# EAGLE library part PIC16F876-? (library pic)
PIC 16F876, 28 pin, 8K prog, 256 EEPROM, USART, MSSP, 2 CCP, timer 0-2, 5x 10-bit A/D, 368 RAM

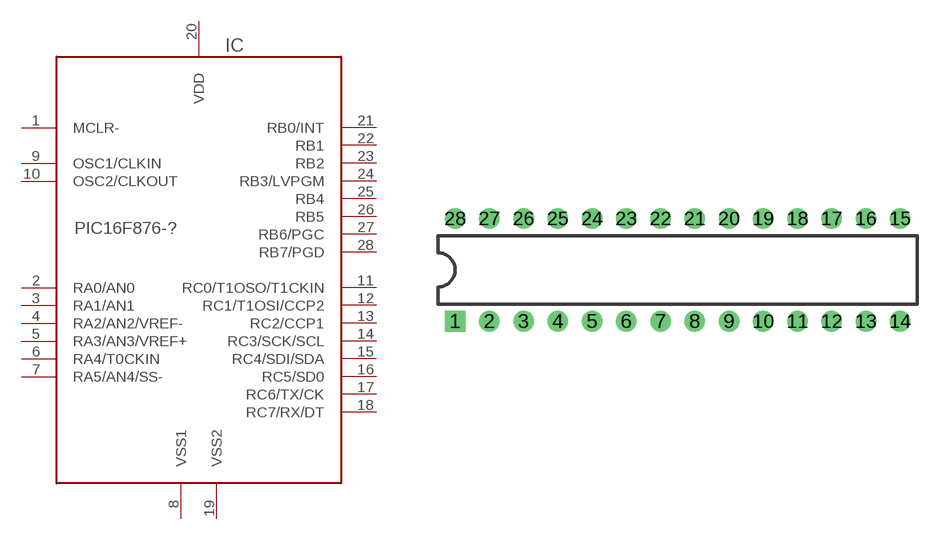
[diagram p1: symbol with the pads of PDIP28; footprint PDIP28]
Designator prefix IC

## PIC16F876-SP  [PDIP28]
1  MCLR-  in
2  RA0/AN0
3  RA1/AN1
4  RA2/AN2/VREF-
5  RA3/AN3/VREF+
6  RA4/T0CKIN  oc
7  RA5/AN4/SS-
8  VSS1  pwr
9  OSC1/CLKIN  in
10  OSC2/CLKOUT  out
11  RC0/T1OSO/T1CKIN
12  RC1/T1OSI/CCP2
13  RC2/CCP1
14  RC3/SCK/SCL
15  RC4/SDI/SDA
16  RC5/SD0
17  RC6/TX/CK
18  RC7/RX/DT
19  VSS2  pwr
20  VDD  pwr
21  RB0/INT
22  RB1
23  RB2
24  RB3/LVPGM
25  RB4
26  RB5
27  RB6/PGC
28  RB7/PGD

## Footprint PDIP28 (pad centres in mm)
28 pin skinny DIP (SP suffix)
drill 0.737 pad 1.524 square: 1 -17.78,-3.81
drill 0.737 pad 1.524 round: 2 -15.24,-3.81; 3 -12.7,-3.81; 4 -10.16,-3.81; 5 -7.62,-3.81; 6 -5.08,-3.81; 7 -2.54,-3.81; 8 0,-3.81; 9 2.54,-3.81; 10 5.08,-3.81; 11 7.62,-3.81; 12 10.16,-3.81; 13 12.7,-3.81; 14 15.24,-3.81; 15 15.24,3.81; 16 12.7,3.81; 17 10.16,3.81; 18 7.62,3.81; 19 5.08,3.81; 20 2.54,3.81; 21 0,3.81; 22 -2.54,3.81; 23 -5.08,3.81; 24 -7.62,3.81; 25 -10.16,3.81; 26 -12.7,3.81; 27 -15.24,3.81; 28 -17.78,3.81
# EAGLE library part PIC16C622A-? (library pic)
18/20 pin, 2K prog, 2 comp, 128 RAM

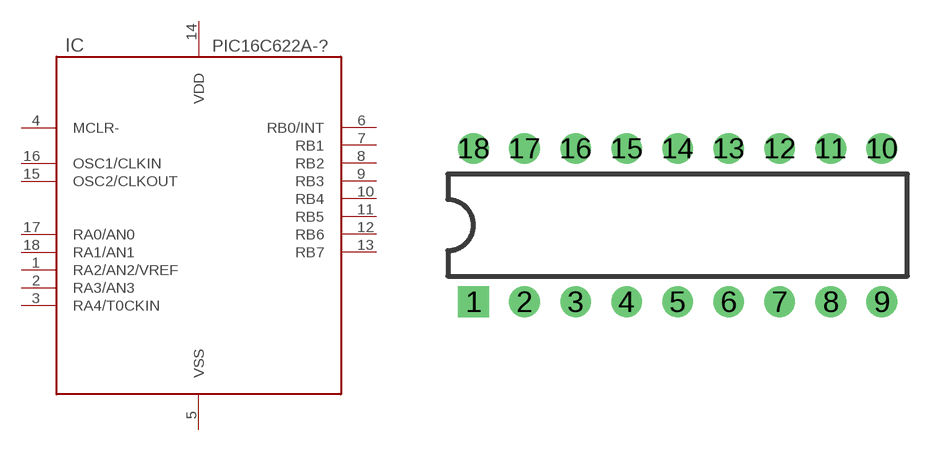
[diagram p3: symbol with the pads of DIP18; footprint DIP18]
Designator prefix IC

## PIC16C622A-P  [DIP18]
1  RA2/AN2/VREF
2  RA3/AN3
3  RA4/T0CKIN
4  MCLR-  in
5  VSS  pwr
6  RB0/INT
7  RB1
8  RB2
9  RB3
10  RB4
11  RB5
12  RB6
13  RB7
14  VDD  pwr
15  OSC2/CLKOUT  out
16  OSC1/CLKIN  in
17  RA0/AN0
18  RA1/AN1

## Footprint DIP18 (pad centres in mm)
18 pin DIP package, P suffix
drill 0.737 pad 1.524 square: 1 -10.16,-3.81
drill 0.737 pad 1.524 round: 2 -7.62,-3.81; 3 -5.08,-3.81; 4 -2.54,-3.81; 5 0,-3.81; 6 2.54,-3.81; 7 5.08,-3.81; 8 7.62,-3.81; 9 10.16,-3.81; 10 10.16,3.81; 11 7.62,3.81; 12 5.08,3.81; 13 2.54,3.81; 14 0,3.81; 15 -2.54,3.81; 16 -5.08,3.81; 17 -7.62,3.81; 18 -10.16,3.81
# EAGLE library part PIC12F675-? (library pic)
8 pins, 1K prog, 128 EEPROM, 1 comp, A/D

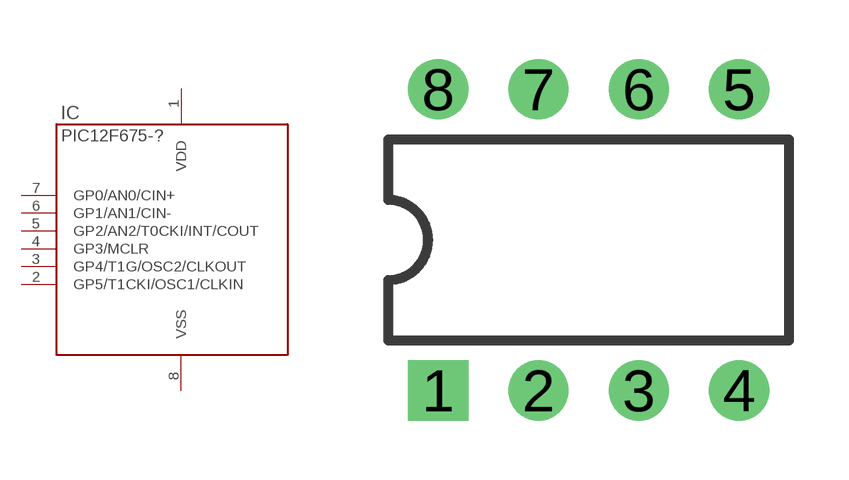
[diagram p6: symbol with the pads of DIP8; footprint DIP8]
Designator prefix IC

## PIC12F675-P  [DIP8]
1  VDD  pwr
2  GP5/T1CKI/OSC1/CLKIN
3  GP4/T1G/OSC2/CLKOUT
4  GP3/MCLR  in
5  GP2/AN2/T0CKI/INT/COUT
6  GP1/AN1/CIN-
7  GP0/AN0/CIN+
8  VSS  pwr

## Footprint DIP8 (pad centres in mm)
8 Pin DIP
drill 0.737 pad 1.524 square: 1 -3.81,-3.81
drill 0.737 pad 1.524 round: 2 -1.27,-3.81; 3 1.27,-3.81; 4 3.81,-3.81; 5 3.81,3.81; 6 1.27,3.81; 7 -1.27,3.81; 8 -3.81,3.81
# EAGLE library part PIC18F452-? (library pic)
18F452, 40 pin, 32Kb prog, 1536b data, 256 EEPROM USART, MSSP, 2 CCP, 8x 10 bit A/D

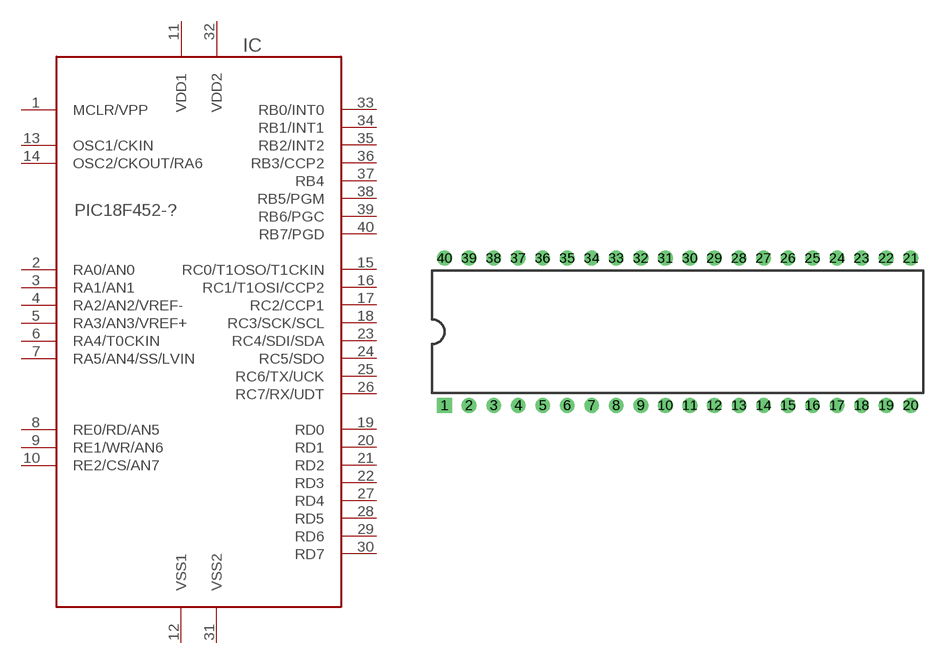
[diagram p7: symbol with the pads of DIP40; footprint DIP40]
Designator prefix IC

## PIC18F452-P  [DIP40]
1  MCLR/VPP  in
2  RA0/AN0
3  RA1/AN1
4  RA2/AN2/VREF-
5  RA3/AN3/VREF+
6  RA4/T0CKIN  oc
7  RA5/AN4/SS/LVIN
8  RE0/RD/AN5
9  RE1/WR/AN6
10  RE2/CS/AN7
11  VDD1  pwr
12  VSS1  pwr
13  OSC1/CKIN  in
14  OSC2/CKOUT/RA6  out
15  RC0/T1OSO/T1CKIN
16  RC1/T1OSI/CCP2
17  RC2/CCP1
18  RC3/SCK/SCL
19  RD0
20  RD1
21  RD2
22  RD3
23  RC4/SDI/SDA
24  RC5/SDO
25  RC6/TX/UCK
26  RC7/RX/UDT
27  RD4
28  RD5
29  RD6
30  RD7
31  VSS2  pwr
32  VDD2  pwr
33  RB0/INT0
34  RB1/INT1
35  RB2/INT2
36  RB3/CCP2
37  RB4
38  RB5/PGM
39  RB6/PGC
40  RB7/PGD

## Footprint DIP40 (pad centres in mm)
40 pin DIP, P or PL suffix
drill 0.737 pad 1.524 square: 1 -24.13,-7.62
drill 0.737 pad 1.524 round: 2 -21.59,-7.62; 3 -19.05,-7.62; 4 -16.51,-7.62; 5 -13.97,-7.62; 6 -11.43,-7.62; 7 -8.89,-7.62; 8 -6.35,-7.62; 9 -3.81,-7.62; 10 -1.27,-7.62; 11 1.27,-7.62; 12 3.81,-7.62; 13 6.35,-7.62; 14 8.89,-7.62; 15 11.43,-7.62; 16 13.97,-7.62; 17 16.51,-7.62; 18 19.05,-7.62; 19 21.59,-7.62; 20 24.13,-7.62; 21 24.13,7.62; 22 21.59,7.62; 23 19.05,7.62; 24 16.51,7.62; 25 13.97,7.62; 26 11.43,7.62; 27 8.89,7.62; 28 6.35,7.62; 29 3.81,7.62; 30 1.27,7.62; 31 -1.27,7.62; 32 -3.81,7.62; 33 -6.35,7.62; 34 -8.89,7.62; 35 -11.43,7.62; 36 -13.97,7.62; 37 -16.51,7.62; 38 -19.05,7.62; 39 -21.59,7.62; 40 -24.13,7.62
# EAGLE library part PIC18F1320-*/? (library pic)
18/20 pins, 4K prog, 256 EEPROM, 7 A/D, USART, CCP, 256 RAM

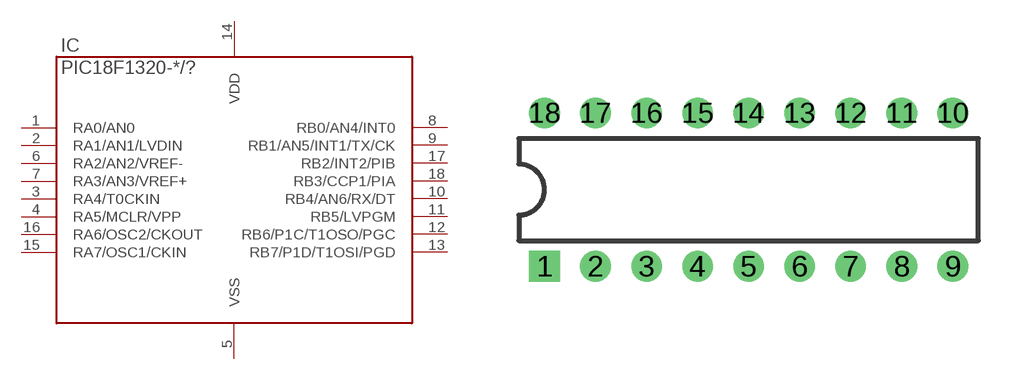
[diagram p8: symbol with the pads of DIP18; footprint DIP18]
Designator prefix IC

## PIC18F1320-E/P, PIC18F1320-I/P  [DIP18]
1  RA0/AN0
2  RA1/AN1/LVDIN
3  RA4/T0CKIN
4  RA5/MCLR/VPP  in
5  VSS  pwr
6  RA2/AN2/VREF-
7  RA3/AN3/VREF+
8  RB0/AN4/INT0
9  RB1/AN5/INT1/TX/CK
10  RB4/AN6/RX/DT
11  RB5/LVPGM
12  RB6/P1C/T1OSO/PGC
13  RB7/P1D/T1OSI/PGD
14  VDD  pwr
15  RA7/OSC1/CKIN
16  RA6/OSC2/CKOUT
17  RB2/INT2/PIB
18  RB3/CCP1/PIA

## Footprint DIP18 (pad centres in mm)
18 pin DIP package, P suffix
drill 0.737 pad 1.524 square: 1 -10.16,-3.81
drill 0.737 pad 1.524 round: 2 -7.62,-3.81; 3 -5.08,-3.81; 4 -2.54,-3.81; 5 0,-3.81; 6 2.54,-3.81; 7 5.08,-3.81; 8 7.62,-3.81; 9 10.16,-3.81; 10 10.16,3.81; 11 7.62,3.81; 12 5.08,3.81; 13 2.54,3.81; 14 0,3.81; 15 -2.54,3.81; 16 -5.08,3.81; 17 -7.62,3.81; 18 -10.16,3.81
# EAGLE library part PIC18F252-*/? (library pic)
18F252, 28 pin, 32Kb prog, 1536 data, 256 EEPROM

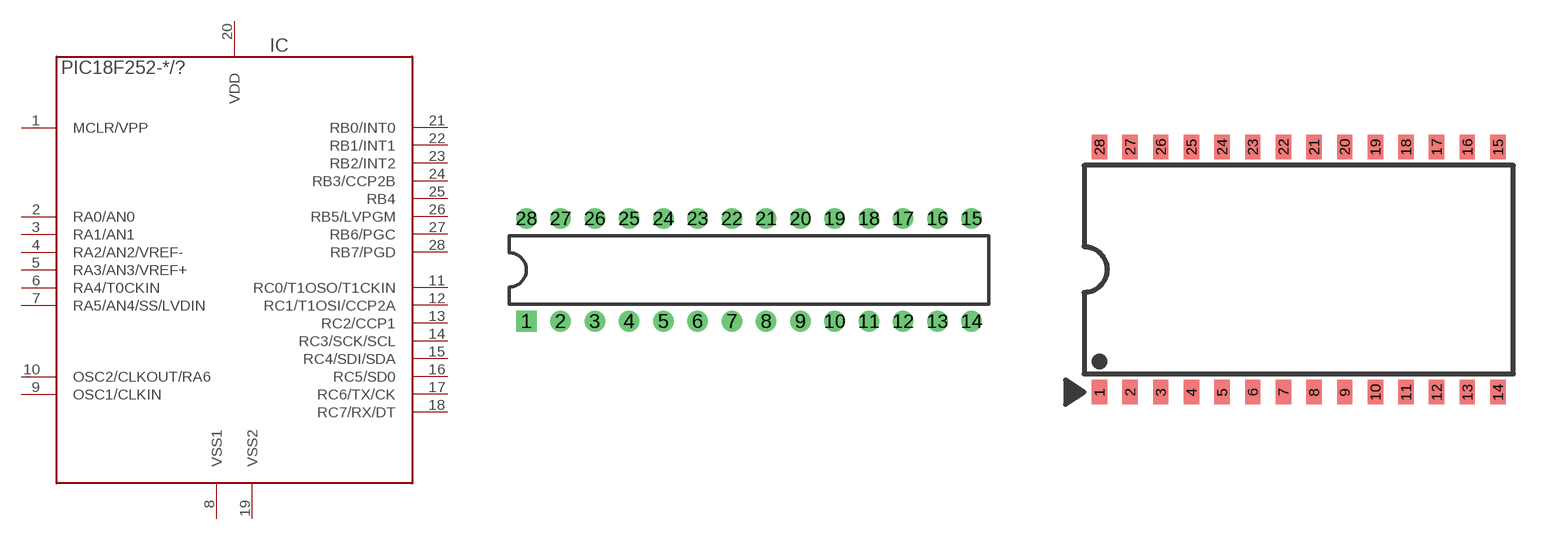
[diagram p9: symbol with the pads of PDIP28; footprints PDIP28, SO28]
Designator prefix IC

## PIC18F252-E/P, PIC18F252-I/P  [PDIP28]
1  MCLR/VPP  in
2  RA0/AN0
3  RA1/AN1
4  RA2/AN2/VREF-
5  RA3/AN3/VREF+
6  RA4/T0CKIN  oc
7  RA5/AN4/SS/LVDIN
8  VSS1  pwr
9  OSC1/CLKIN  in
10  OSC2/CLKOUT/RA6  out
11  RC0/T1OSO/T1CKIN
12  RC1/T1OSI/CCP2A
13  RC2/CCP1
14  RC3/SCK/SCL
15  RC4/SDI/SDA
16  RC5/SD0
17  RC6/TX/CK
18  RC7/RX/DT
19  VSS2  pwr
20  VDD  pwr
21  RB0/INT0
22  RB1/INT1
23  RB2/INT2
24  RB3/CCP2B
25  RB4
26  RB5/LVPGM
27  RB6/PGC
28  RB7/PGD

## PIC18F252-E/SO, PIC18F252-I/SO  [SO28]
Pads as for PDIP28

## Footprint PDIP28 (pad centres in mm)
28 pin skinny DIP (SP suffix)
drill 0.737 pad 1.524 square: 1 -17.78,-3.81
drill 0.737 pad 1.524 round: 2 -15.24,-3.81; 3 -12.7,-3.81; 4 -10.16,-3.81; 5 -7.62,-3.81; 6 -5.08,-3.81; 7 -2.54,-3.81; 8 0,-3.81; 9 2.54,-3.81; 10 5.08,-3.81; 11 7.62,-3.81; 12 10.16,-3.81; 13 12.7,-3.81; 14 15.24,-3.81; 15 15.24,3.81; 16 12.7,3.81; 17 10.16,3.81; 18 7.62,3.81; 19 5.08,3.81; 20 2.54,3.81; 21 0,3.81; 22 -2.54,3.81; 23 -5.08,3.81; 24 -7.62,3.81; 25 -10.16,3.81; 26 -12.7,3.81; 27 -15.24,3.81; 28 -17.78,3.81

## Footprint SO28 (pad centres in mm)
28 pin SOIC
smd 0.635 x 1.016: 1 -8.255,-5.08; 2 -6.985,-5.08; 3 -5.715,-5.08; 4 -4.445,-5.08; 5 -3.175,-5.08; 6 -1.905,-5.08; 7 -0.635,-5.08; 8 0.635,-5.08; 9 1.905,-5.08; 10 3.175,-5.08; 11 4.445,-5.08; 12 5.715,-5.08; 13 6.985,-5.08; 14 8.255,-5.08; 15 8.255,5.08; 16 6.985,5.08; 17 5.715,5.08; 18 4.445,5.08; 19 3.175,5.08; 20 1.905,5.08; 21 0.635,5.08; 22 -0.635,5.08; 23 -1.905,5.08; 24 -3.175,5.08; 25 -4.445,5.08; 26 -5.715,5.08; 27 -6.985,5.08; 28 -8.255,5.08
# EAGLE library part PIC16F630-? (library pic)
14 pins, 1K prog, 128 EEPROM, comp, 64 RAM

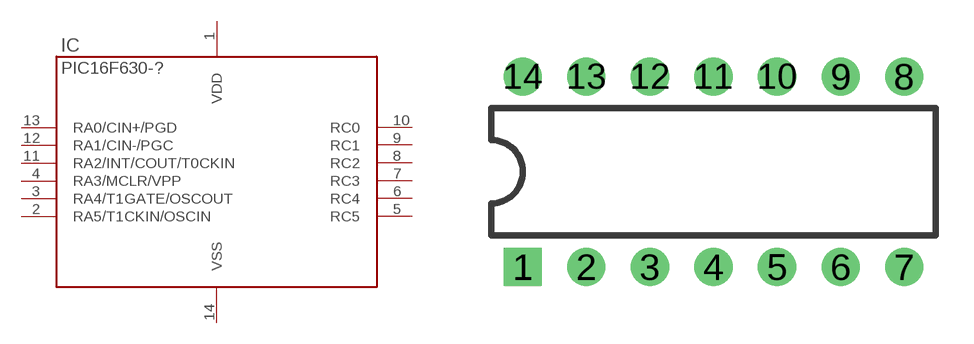
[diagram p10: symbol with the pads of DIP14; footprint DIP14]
Designator prefix IC

## PIC16F630-I/P  [DIP14]
1  VDD  pwr
2  RA5/T1CKIN/OSCIN
3  RA4/T1GATE/OSCOUT
4  RA3/MCLR/VPP  in
5  RC5
6  RC4
7  RC3
8  RC2
9  RC1
10  RC0
11  RA2/INT/COUT/T0CKIN
12  RA1/CIN-/PGC
13  RA0/CIN+/PGD
14  VSS  pwr

## Footprint DIP14 (pad centres in mm)
14 pin DIP package, P suffix
drill 0.737 pad 1.524 square: 1 -7.62,-3.81
drill 0.737 pad 1.524 round: 2 -5.08,-3.81; 3 -2.54,-3.81; 4 0,-3.81; 5 2.54,-3.81; 6 5.08,-3.81; 7 7.62,-3.81; 8 7.62,3.81; 9 5.08,3.81; 10 2.54,3.81; 11 0,3.81; 12 -2.54,3.81; 13 -5.08,3.81; 14 -7.62,3.81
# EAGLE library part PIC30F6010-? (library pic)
dsPIC, 80 pin, 48Kw prog, 8Kb RAM, 4Kb EEPROM, 16 A/D, 8 MPWM, 2 UART 2 CAN, 1 IIC, 2 SPI, 8 PWM, 8 capture

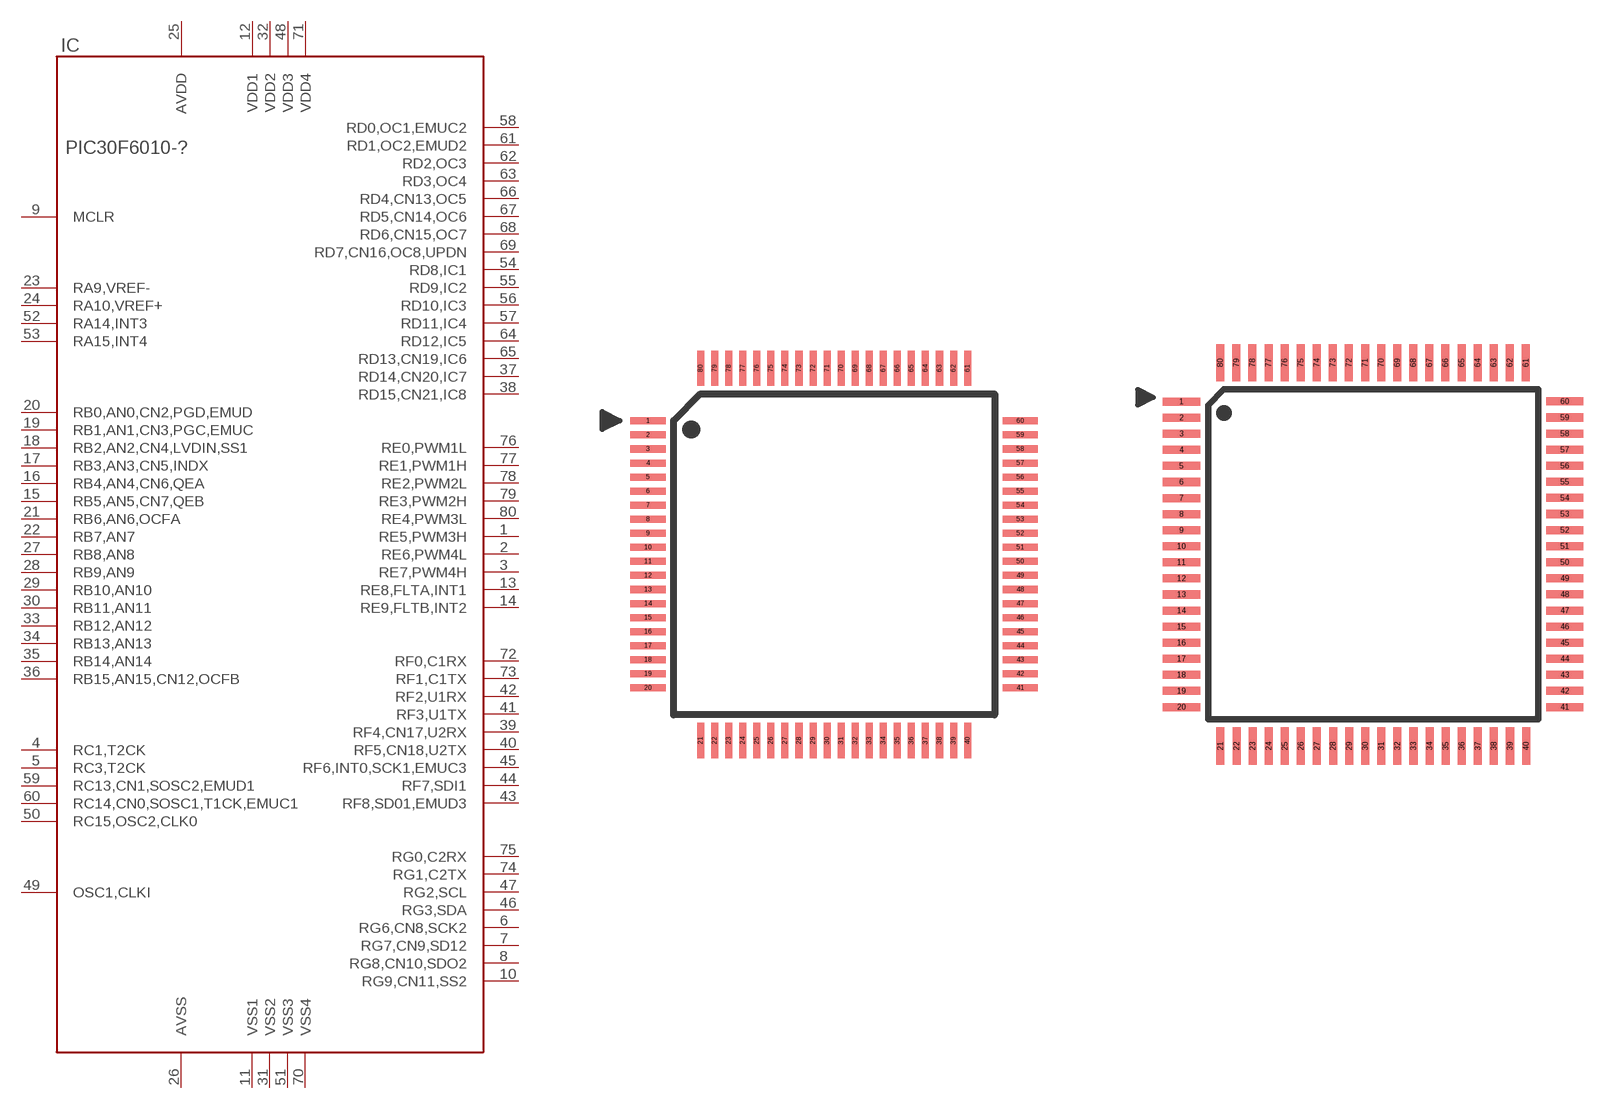
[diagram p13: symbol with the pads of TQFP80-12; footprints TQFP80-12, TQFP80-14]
Designator prefix IC

## PIC30F6010-PT  [TQFP80-12]
1  RE5,PWM3H
2  RE6,PWM4L
3  RE7,PWM4H
4  RC1,T2CK
5  RC3,T2CK
6  RG6,CN8,SCK2
7  RG7,CN9,SD12
8  RG8,CN10,SDO2
9  MCLR  in
10  RG9,CN11,SS2
11  VSS1  pwr
12  VDD1  pwr
13  RE8,FLTA,INT1
14  RE9,FLTB,INT2
15  RB5,AN5,CN7,QEB
16  RB4,AN4,CN6,QEA
17  RB3,AN3,CN5,INDX
18  RB2,AN2,CN4,LVDIN,SS1
19  RB1,AN1,CN3,PGC,EMUC
20  RB0,AN0,CN2,PGD,EMUD
21  RB6,AN6,OCFA
22  RB7,AN7
23  RA9,VREF-
24  RA10,VREF+
25  AVDD  pwr
26  AVSS  pwr
27  RB8,AN8
28  RB9,AN9
29  RB10,AN10
30  RB11,AN11
31  VSS2  pwr
32  VDD2  pwr
33  RB12,AN12
34  RB13,AN13
35  RB14,AN14
36  RB15,AN15,CN12,OCFB
37  RD14,CN20,IC7
38  RD15,CN21,IC8
39  RF4,CN17,U2RX
40  RF5,CN18,U2TX
41  RF3,U1TX
42  RF2,U1RX
43  RF8,SD01,EMUD3
44  RF7,SDI1
45  RF6,INT0,SCK1,EMUC3
46  RG3,SDA
47  RG2,SCL
48  VDD3  pwr
49  OSC1,CLKI
50  RC15,OSC2,CLK0
51  VSS3  pwr
52  RA14,INT3
53  RA15,INT4
54  RD8,IC1
55  RD9,IC2
56  RD10,IC3
57  RD11,IC4
58  RD0,OC1,EMUC2
59  RC13,CN1,SOSC2,EMUD1
60  RC14,CN0,SOSC1,T1CK,EMUC1
61  RD1,OC2,EMUD2
62  RD2,OC3
63  RD3,OC4
64  RD12,IC5
65  RD13,CN19,IC6
66  RD4,CN13,OC5
67  RD5,CN14,OC6
68  RD6,CN15,OC7
69  RD7,CN16,OC8,UPDN
70  VSS4  pwr
71  VDD4  pwr
72  RF0,C1RX
73  RF1,C1TX
74  RG1,C2TX
75  RG0,C2RX
76  RE0,PWM1L
77  RE1,PWM1H
78  RE2,PWM2L
79  RE3,PWM2H
80  RE4,PWM3L

## PIC30F6010-PF  [TQFP80-14]
Pads as for TQFP80-12

## Footprint TQFP80-12 (pad centres in mm)
80 pin TQFP 12x12mm (PT suffix)
smd 1.25 x 0.25: 1 -6.625,4.75; 2 -6.625,4.25; 3 -6.625,3.75; 4 -6.625,3.25; 5 -6.625,2.75; 6 -6.625,2.25; 7 -6.625,1.75; 8 -6.625,1.25; 9 -6.625,0.75; 10 -6.625,0.25; 11 -6.625,-0.25; 12 -6.625,-0.75; 13 -6.625,-1.25; 14 -6.625,-1.75; 15 -6.625,-2.25; 16 -6.625,-2.75; 17 -6.625,-3.25; 18 -6.625,-3.75; 19 -6.625,-4.25; 20 -6.625,-4.75; 41 6.625,-4.75; 42 6.625,-4.25; 43 6.625,-3.75; 44 6.625,-3.25; 45 6.625,-2.75; 46 6.625,-2.25; 47 6.625,-1.75; 48 6.625,-1.25; 49 6.625,-0.75; 50 6.625,-0.25; 51 6.625,0.25; 52 6.625,0.75; 53 6.625,1.25; 54 6.625,1.75; 55 6.625,2.25; 56 6.625,2.75; 57 6.625,3.25; 58 6.625,3.75; 59 6.625,4.25; 60 6.625,4.75
smd 0.25 x 1.25: 21 -4.75,-6.625; 22 -4.25,-6.625; 23 -3.75,-6.625; 24 -3.25,-6.625; 25 -2.75,-6.625; 26 -2.25,-6.625; 27 -1.75,-6.625; 28 -1.25,-6.625; 29 -0.75,-6.625; 30 -0.25,-6.625; 31 0.25,-6.625; 32 0.75,-6.625; 33 1.25,-6.625; 34 1.75,-6.625; 35 2.25,-6.625; 36 2.75,-6.625; 37 3.25,-6.625; 38 3.75,-6.625; 39 4.25,-6.625; 40 4.75,-6.625; 61 4.75,6.625; 62 4.25,6.625; 63 3.75,6.625; 64 3.25,6.625; 65 2.75,6.625; 66 2.25,6.625; 67 1.75,6.625; 68 1.25,6.625; 69 0.75,6.625; 70 0.25,6.625; 71 -0.25,6.625; 72 -0.75,6.625; 73 -1.25,6.625; 74 -1.75,6.625; 75 -2.25,6.625; 76 -2.75,6.625; 77 -3.25,6.625; 78 -3.75,6.625; 79 -4.25,6.625; 80 -4.75,6.625

## Footprint TQFP80-14 (pad centres in mm)
80 pin TQFP 14x14mm (PF suffix)
smd 1.5 x 0.325: 1 -7.75,6.175; 2 -7.75,5.525; 3 -7.75,4.875; 4 -7.75,4.225; 5 -7.75,3.575; 6 -7.75,2.925; 7 -7.75,2.275; 8 -7.75,1.625; 9 -7.75,0.975; 10 -7.75,0.325; 11 -7.75,-0.325; 12 -7.75,-0.975; 13 -7.75,-1.625; 14 -7.75,-2.275; 15 -7.75,-2.925; 16 -7.75,-3.575; 17 -7.75,-4.225; 18 -7.75,-4.875; 19 -7.75,-5.525; 20 -7.75,-6.175; 41 7.75,-6.175; 42 7.75,-5.525; 43 7.75,-4.874; 44 7.75,-4.224; 45 7.75,-3.573; 46 7.75,-2.923; 47 7.75,-2.273; 48 7.75,-1.622; 49 7.75,-0.972; 50 7.75,-0.321; 51 7.75,0.329; 52 7.75,0.979; 53 7.75,1.63; 54 7.75,2.28; 55 7.75,2.931; 56 7.75,3.581; 57 7.75,4.231; 58 7.75,4.882; 59 7.75,5.532; 60 7.75,6.183
smd 0.325 x 1.5: 21 -6.175,-7.75; 22 -5.525,-7.75; 23 -4.874,-7.75; 24 -4.224,-7.75; 25 -3.573,-7.75; 26 -2.923,-7.75; 27 -2.273,-7.75; 28 -1.622,-7.75; 29 -0.972,-7.75; 30 -0.321,-7.75; 31 0.329,-7.75; 32 0.979,-7.75; 33 1.63,-7.75; 34 2.28,-7.75; 35 2.931,-7.75; 36 3.581,-7.75; 37 4.231,-7.75; 38 4.882,-7.75; 39 5.532,-7.75; 40 6.183,-7.75; 61 6.175,7.75; 62 5.525,7.75; 63 4.874,7.75; 64 4.224,7.75; 65 3.573,7.75; 66 2.923,7.75; 67 2.273,7.75; 68 1.622,7.75; 69 0.972,7.75; 70 0.321,7.75; 71 -0.329,7.75; 72 -0.979,7.75; 73 -1.63,7.75; 74 -2.28,7.75; 75 -2.931,7.75; 76 -3.581,7.75; 77 -4.231,7.75; 78 -4.882,7.75; 79 -5.532,7.75; 80 -6.183,7.75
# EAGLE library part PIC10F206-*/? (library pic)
6 pins, 512 prog, 24 RAM, comparator

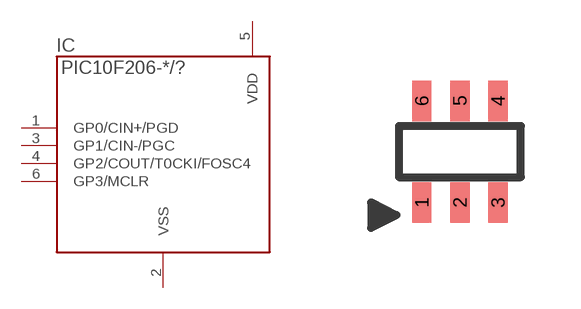
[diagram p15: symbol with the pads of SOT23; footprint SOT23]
Designator prefix IC

## PIC10F206-E/OT, PIC10F206-I/OT  [SOT23]
1  GP0/CIN+/PGD
2  VSS  pwr
3  GP1/CIN-/PGC
4  GP2/COUT/T0CKI/FOSC4
5  VDD  pwr
6  GP3/MCLR  in

## Footprint SOT23 (pad centres in mm)
Standard SOT-23, 2 rows of 3 pins, .0375 pin pitch
smd 0.483 x 1.016: 1 -0.953,-1.27; 2 0,-1.27; 3 0.953,-1.27; 4 0.953,1.27; 5 0,1.27; 6 -0.953,1.27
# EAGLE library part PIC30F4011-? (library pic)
dsPIC, 40/44 pin, 16Kw prog, 2Kb RAM, 1Kb EEPROM, 9 A/D, 2 MPWM, 2 UART

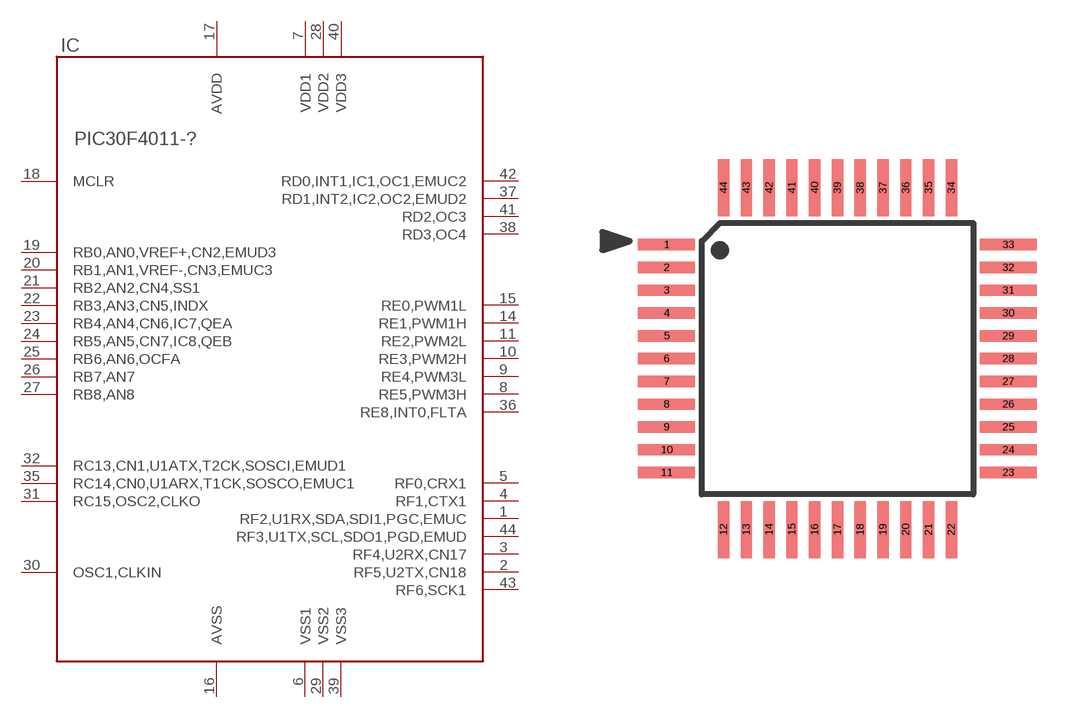
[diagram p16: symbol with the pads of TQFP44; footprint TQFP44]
Designator prefix IC

## PIC30F4011-PT  [TQFP44]
1  RF2,U1RX,SDA,SDI1,PGC,EMUC
2  RF5,U2TX,CN18
3  RF4,U2RX,CN17
4  RF1,CTX1
5  RF0,CRX1
6  VSS1  pwr
7  VDD1  pwr
8  RE5,PWM3H
9  RE4,PWM3L
10  RE3,PWM2H
11  RE2,PWM2L
14  RE1,PWM1H
15  RE0,PWM1L
16  AVSS  pwr
17  AVDD  pwr
18  MCLR  in
19  RB0,AN0,VREF+,CN2,EMUD3
20  RB1,AN1,VREF-,CN3,EMUC3
21  RB2,AN2,CN4,SS1
22  RB3,AN3,CN5,INDX
23  RB4,AN4,CN6,IC7,QEA
24  RB5,AN5,CN7,IC8,QEB
25  RB6,AN6,OCFA
26  RB7,AN7
27  RB8,AN8
28  VDD2  pwr
29  VSS2  pwr
30  OSC1,CLKIN  in
31  RC15,OSC2,CLKO
32  RC13,CN1,U1ATX,T2CK,SOSCI,EMUD1
35  RC14,CN0,U1ARX,T1CK,SOSCO,EMUC1
36  RE8,INT0,FLTA
37  RD1,INT2,IC2,OC2,EMUD2
38  RD3,OC4
39  VSS3  pwr
40  VDD3  pwr
41  RD2,OC3
42  RD0,INT1,IC1,OC1,EMUC2
43  RF6,SCK1
44  RF3,U1TX,SCL,SDO1,PGD,EMUD

## Footprint TQFP44 (pad centres in mm)
44 pin TQFP 10x10mm (PT suffix}
smd 2 x 0.4: 1 -6,4; 2 -6,3.2; 3 -6,2.4; 4 -6,1.6; 5 -6,0.8; 6 -6,0; 7 -6,-0.8; 8 -6,-1.6; 9 -6,-2.4; 10 -6,-3.2; 11 -6,-4; 23 6,-4; 24 6,-3.2; 25 6,-2.4; 26 6,-1.6; 27 6,-0.8; 28 6,0; 29 6,0.8; 30 6,1.6; 31 6,2.4; 32 6,3.2; 33 6,4
smd 0.4 x 2: 12 -4,-6; 13 -3.2,-6; 14 -2.4,-6; 15 -1.6,-6; 16 -0.8,-6; 17 0,-6; 18 0.8,-6; 19 1.6,-6; 20 2.4,-6; 21 3.2,-6; 22 4,-6; 34 4,6; 35 3.2,6; 36 2.4,6; 37 1.6,6; 38 0.8,6; 39 0,6; 40 -0.8,6; 41 -1.6,6; 42 -2.4,6; 43 -3.2,6; 44 -4,6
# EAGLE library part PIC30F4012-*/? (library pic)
dsPIC, 28 pin, 16Kw prog, 2Kb RAM, 1Kb EEPROM, 6 A/D, 2 MPWM, 1 UART

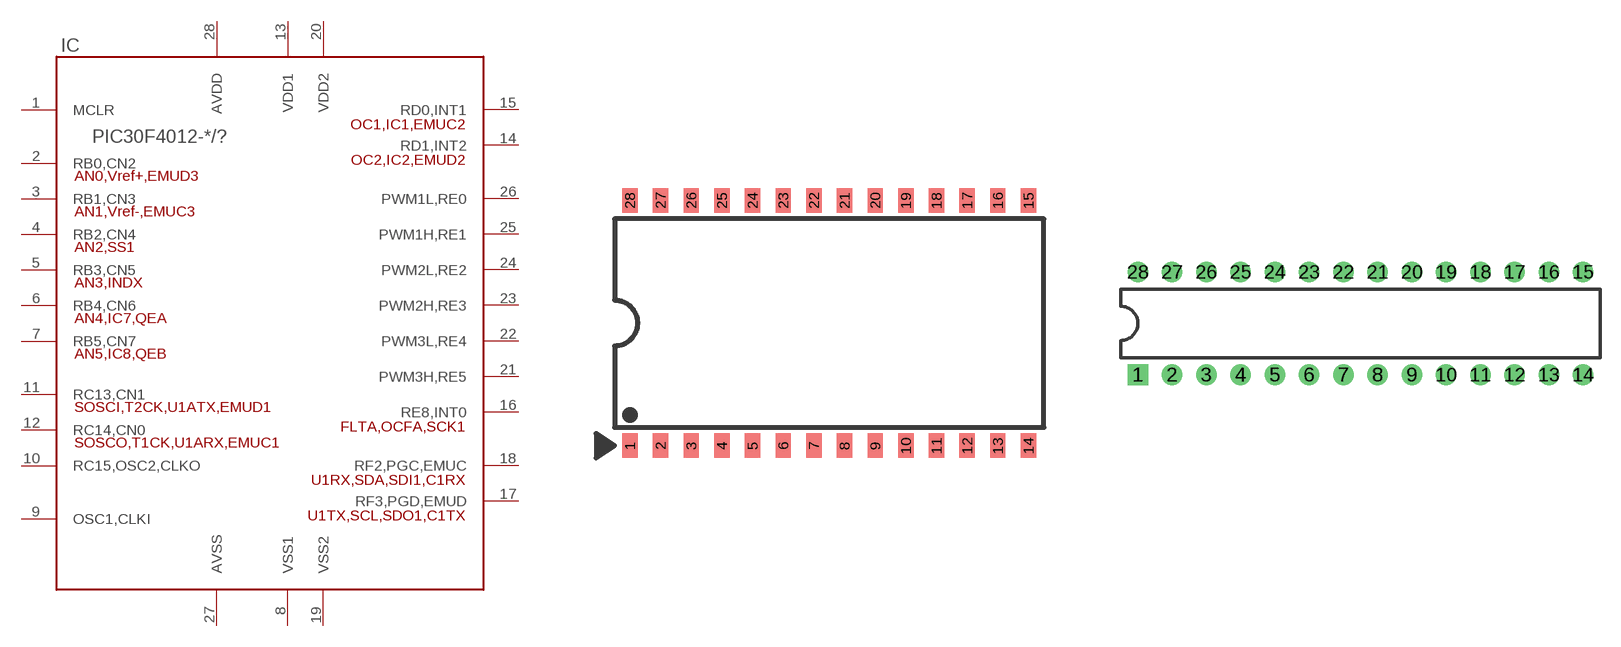
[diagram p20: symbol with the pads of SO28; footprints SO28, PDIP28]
Designator prefix IC

## PIC30F4012-20E/SO, PIC30F4012-20I/SO, PIC30F4012-30E/SO, PIC30F4012-30I/SO  [SO28]
1  MCLR  in
2  RB0,CN2
3  RB1,CN3
4  RB2,CN4
5  RB3,CN5
6  RB4,CN6
7  RB5,CN7
8  VSS1  pwr
9  OSC1,CLKI  in
10  RC15,OSC2,CLKO
11  RC13,CN1
12  RC14,CN0
13  VDD1  pwr
14  RD1,INT2
15  RD0,INT1
16  RE8,INT0
17  RF3,PGD,EMUD
18  RF2,PGC,EMUC
19  VSS2  pwr
20  VDD2  pwr
21  PWM3H,RE5
22  PWM3L,RE4
23  PWM2H,RE3
24  PWM2L,RE2
25  PWM1H,RE1
26  PWM1L,RE0
27  AVSS  pwr
28  AVDD  pwr

## PIC30F4012-20E/SP, PIC30F4012-20I/SP, PIC30F4012-30E/SP, PIC30F4012-30I/SP  [PDIP28]
Pads as for SO28

## Footprint SO28 (pad centres in mm)
28 pin SOIC
smd 0.635 x 1.016: 1 -8.255,-5.08; 2 -6.985,-5.08; 3 -5.715,-5.08; 4 -4.445,-5.08; 5 -3.175,-5.08; 6 -1.905,-5.08; 7 -0.635,-5.08; 8 0.635,-5.08; 9 1.905,-5.08; 10 3.175,-5.08; 11 4.445,-5.08; 12 5.715,-5.08; 13 6.985,-5.08; 14 8.255,-5.08; 15 8.255,5.08; 16 6.985,5.08; 17 5.715,5.08; 18 4.445,5.08; 19 3.175,5.08; 20 1.905,5.08; 21 0.635,5.08; 22 -0.635,5.08; 23 -1.905,5.08; 24 -3.175,5.08; 25 -4.445,5.08; 26 -5.715,5.08; 27 -6.985,5.08; 28 -8.255,5.08

## Footprint PDIP28 (pad centres in mm)
28 pin skinny DIP (SP suffix)
drill 0.737 pad 1.524 square: 1 -17.78,-3.81
drill 0.737 pad 1.524 round: 2 -15.24,-3.81; 3 -12.7,-3.81; 4 -10.16,-3.81; 5 -7.62,-3.81; 6 -5.08,-3.81; 7 -2.54,-3.81; 8 0,-3.81; 9 2.54,-3.81; 10 5.08,-3.81; 11 7.62,-3.81; 12 10.16,-3.81; 13 12.7,-3.81; 14 15.24,-3.81; 15 15.24,3.81; 16 12.7,3.81; 17 10.16,3.81; 18 7.62,3.81; 19 5.08,3.81; 20 2.54,3.81; 21 0,3.81; 22 -2.54,3.81; 23 -5.08,3.81; 24 -7.62,3.81; 25 -10.16,3.81; 26 -12.7,3.81; 27 -15.24,3.81; 28 -17.78,3.81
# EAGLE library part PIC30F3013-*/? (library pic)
dsPIC, 28 pin, 8Kw prog, 2Kb RAM, 1Kb EEPROM, 10x 12 bit A/D, 2 UART 1 IIC, 1 SPI, 2 PWM, 2 capture

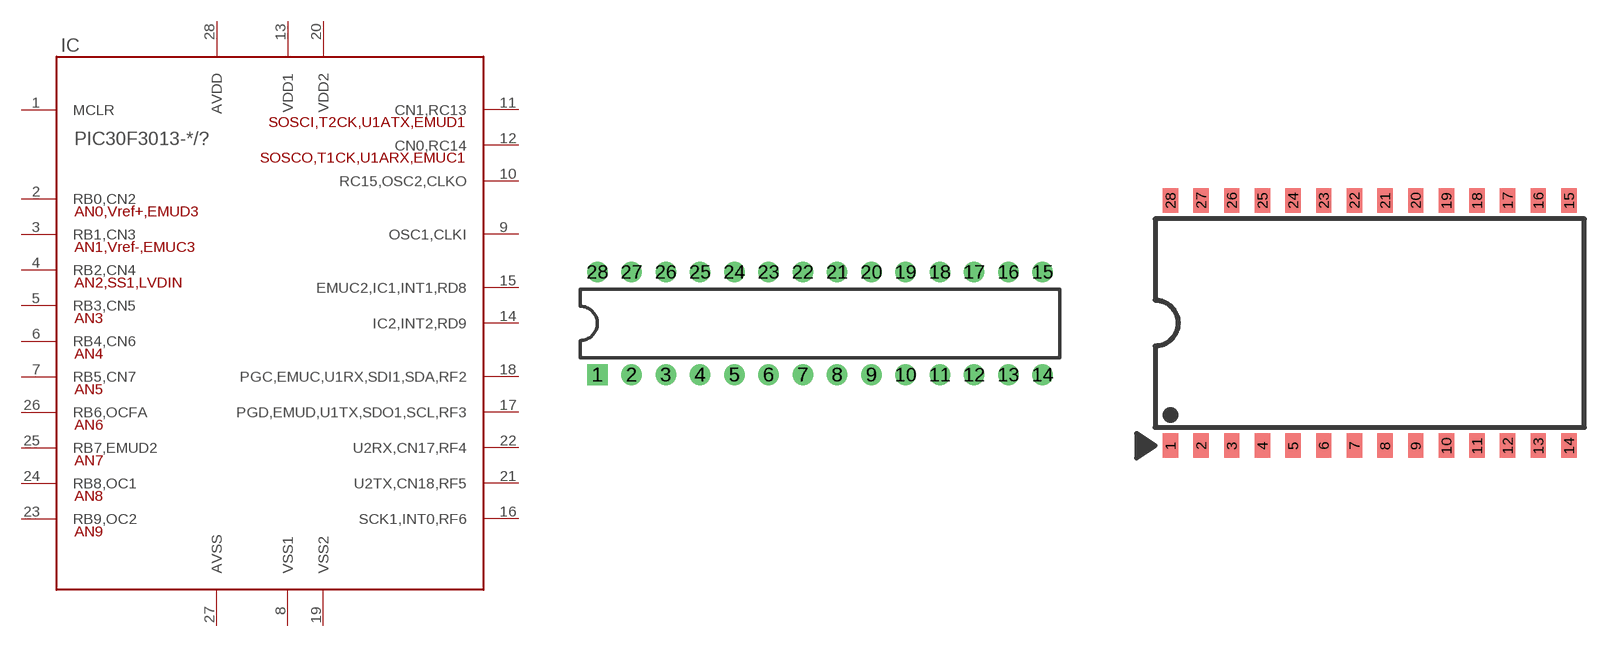
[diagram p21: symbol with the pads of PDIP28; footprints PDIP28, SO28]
Designator prefix IC

## PIC30F3013-E/SP, PIC30F3013-I/SP  [PDIP28]
1  MCLR  in
2  RB0,CN2
3  RB1,CN3
4  RB2,CN4
5  RB3,CN5
6  RB4,CN6
7  RB5,CN7
8  VSS1  pwr
9  OSC1,CLKI  in
10  RC15,OSC2,CLKO
11  CN1,RC13
12  CN0,RC14
13  VDD1  pwr
14  IC2,INT2,RD9
15  EMUC2,IC1,INT1,RD8
16  SCK1,INT0,RF6
17  PGD,EMUD,U1TX,SDO1,SCL,RF3
18  PGC,EMUC,U1RX,SDI1,SDA,RF2
19  VSS2  pwr
20  VDD2  pwr
21  U2TX,CN18,RF5
22  U2RX,CN17,RF4
23  RB9,OC2
24  RB8,OC1
25  RB7,EMUD2
26  RB6,OCFA
27  AVSS  pwr
28  AVDD  pwr

## PIC30F3013-E/SO, PIC30F3013-I/SO  [SO28]
Pads as for PDIP28

## Footprint PDIP28 (pad centres in mm)
28 pin skinny DIP (SP suffix)
drill 0.737 pad 1.524 square: 1 -17.78,-3.81
drill 0.737 pad 1.524 round: 2 -15.24,-3.81; 3 -12.7,-3.81; 4 -10.16,-3.81; 5 -7.62,-3.81; 6 -5.08,-3.81; 7 -2.54,-3.81; 8 0,-3.81; 9 2.54,-3.81; 10 5.08,-3.81; 11 7.62,-3.81; 12 10.16,-3.81; 13 12.7,-3.81; 14 15.24,-3.81; 15 15.24,3.81; 16 12.7,3.81; 17 10.16,3.81; 18 7.62,3.81; 19 5.08,3.81; 20 2.54,3.81; 21 0,3.81; 22 -2.54,3.81; 23 -5.08,3.81; 24 -7.62,3.81; 25 -10.16,3.81; 26 -12.7,3.81; 27 -15.24,3.81; 28 -17.78,3.81

## Footprint SO28 (pad centres in mm)
28 pin SOIC
smd 0.635 x 1.016: 1 -8.255,-5.08; 2 -6.985,-5.08; 3 -5.715,-5.08; 4 -4.445,-5.08; 5 -3.175,-5.08; 6 -1.905,-5.08; 7 -0.635,-5.08; 8 0.635,-5.08; 9 1.905,-5.08; 10 3.175,-5.08; 11 4.445,-5.08; 12 5.715,-5.08; 13 6.985,-5.08; 14 8.255,-5.08; 15 8.255,5.08; 16 6.985,5.08; 17 5.715,5.08; 18 4.445,5.08; 19 3.175,5.08; 20 1.905,5.08; 21 0.635,5.08; 22 -0.635,5.08; 23 -1.905,5.08; 24 -3.175,5.08; 25 -4.445,5.08; 26 -5.715,5.08; 27 -6.985,5.08; 28 -8.255,5.08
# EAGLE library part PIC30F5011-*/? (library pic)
dsPIC, 64 pin, 66KB prog, 4KB RAM, 1KB EEPROM, 16 12b A/D, 52 I/O

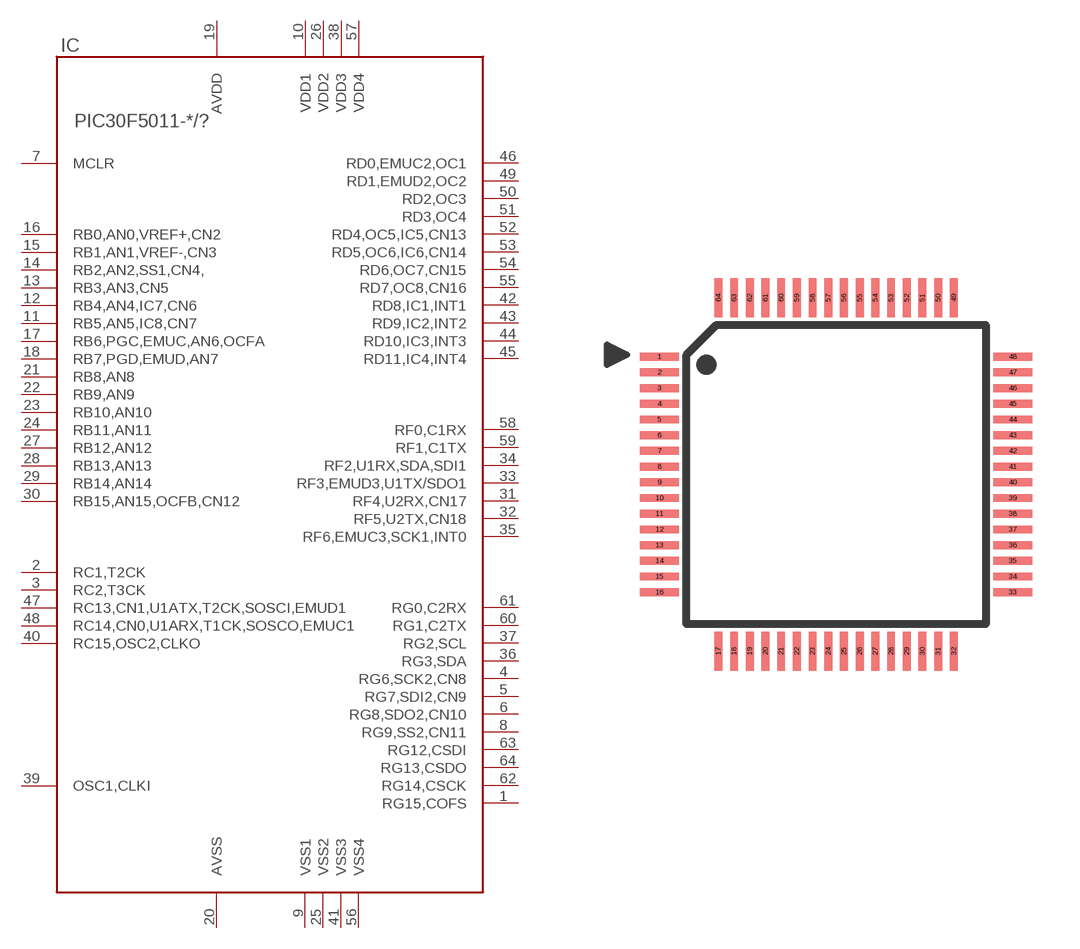
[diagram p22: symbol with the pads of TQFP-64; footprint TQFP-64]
Designator prefix IC

## PIC30F5011-30E/PT, PIC30F5011-30I/PT  [TQFP-64]
1  RG15,COFS
2  RC1,T2CK
3  RC2,T3CK
4  RG6,SCK2,CN8
5  RG7,SDI2,CN9
6  RG8,SDO2,CN10
7  MCLR  in
8  RG9,SS2,CN11
9  VSS1  pwr
10  VDD1  pwr
11  RB5,AN5,IC8,CN7
12  RB4,AN4,IC7,CN6
13  RB3,AN3,CN5
14  RB2,AN2,SS1,CN4,
15  RB1,AN1,VREF-,CN3
16  RB0,AN0,VREF+,CN2
17  RB6,PGC,EMUC,AN6,OCFA
18  RB7,PGD,EMUD,AN7
19  AVDD  pwr
20  AVSS  pwr
21  RB8,AN8
22  RB9,AN9
23  RB10,AN10
24  RB11,AN11
25  VSS2  pwr
26  VDD2  pwr
27  RB12,AN12
28  RB13,AN13
29  RB14,AN14
30  RB15,AN15,OCFB,CN12
31  RF4,U2RX,CN17
32  RF5,U2TX,CN18
33  RF3,EMUD3,U1TX/SDO1
34  RF2,U1RX,SDA,SDI1
35  RF6,EMUC3,SCK1,INT0
36  RG3,SDA
37  RG2,SCL
38  VDD3  pwr
39  OSC1,CLKI  in
40  RC15,OSC2,CLKO
41  VSS3  pwr
42  RD8,IC1,INT1
43  RD9,IC2,INT2
44  RD10,IC3,INT3
45  RD11,IC4,INT4
46  RD0,EMUC2,OC1
47  RC13,CN1,U1ATX,T2CK,SOSCI,EMUD1
48  RC14,CN0,U1ARX,T1CK,SOSCO,EMUC1
49  RD1,EMUD2,OC2
50  RD2,OC3
51  RD3,OC4
52  RD4,OC5,IC5,CN13
53  RD5,OC6,IC6,CN14
54  RD6,OC7,CN15
55  RD7,OC8,CN16
56  VSS4
57  VDD4
58  RF0,C1RX
59  RF1,C1TX
60  RG1,C2TX
61  RG0,C2RX
62  RG14,CSCK
63  RG12,CSDI
64  RG13,CSDO

## Footprint TQFP-64 (pad centres in mm)
64 pin TQFP (PT suffix)
smd 1.25 x 0.25: 1 -5.625,3.75; 2 -5.625,3.25; 3 -5.625,2.75; 4 -5.625,2.25; 5 -5.625,1.75; 6 -5.625,1.25; 7 -5.625,0.75; 8 -5.625,0.25; 9 -5.625,-0.25; 10 -5.625,-0.75; 11 -5.625,-1.25; 12 -5.625,-1.75; 13 -5.625,-2.25; 14 -5.625,-2.75; 15 -5.625,-3.25; 16 -5.625,-3.75; 33 5.625,-3.75; 34 5.625,-3.25; 35 5.625,-2.75; 36 5.625,-2.25; 37 5.625,-1.75; 38 5.625,-1.25; 39 5.625,-0.75; 40 5.625,-0.25; 41 5.625,0.25; 42 5.625,0.75; 43 5.625,1.25; 44 5.625,1.75; 45 5.625,2.25; 46 5.625,2.75; 47 5.625,3.25; 48 5.625,3.75
smd 0.25 x 1.25: 17 -3.75,-5.625; 18 -3.25,-5.625; 19 -2.75,-5.625; 20 -2.25,-5.625; 21 -1.75,-5.625; 22 -1.25,-5.625; 23 -0.75,-5.625; 24 -0.25,-5.625; 25 0.25,-5.625; 26 0.75,-5.625; 27 1.25,-5.625; 28 1.75,-5.625; 29 2.25,-5.625; 30 2.75,-5.625; 31 3.25,-5.625; 32 3.75,-5.625; 49 3.75,5.625; 50 3.25,5.625; 51 2.75,5.625; 52 2.25,5.625; 53 1.75,5.625; 54 1.25,5.625; 55 0.75,5.625; 56 0.25,5.625; 57 -0.25,5.625; 58 -0.75,5.625; 59 -1.25,5.625; 60 -1.75,5.625; 61 -2.25,5.625; 62 -2.75,5.625; 63 -3.25,5.625; 64 -3.75,5.625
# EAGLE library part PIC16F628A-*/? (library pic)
18/20 pins, 2K prog, 224 RAM, 128 EEPROM, UART, 2 comp, 1 CCP

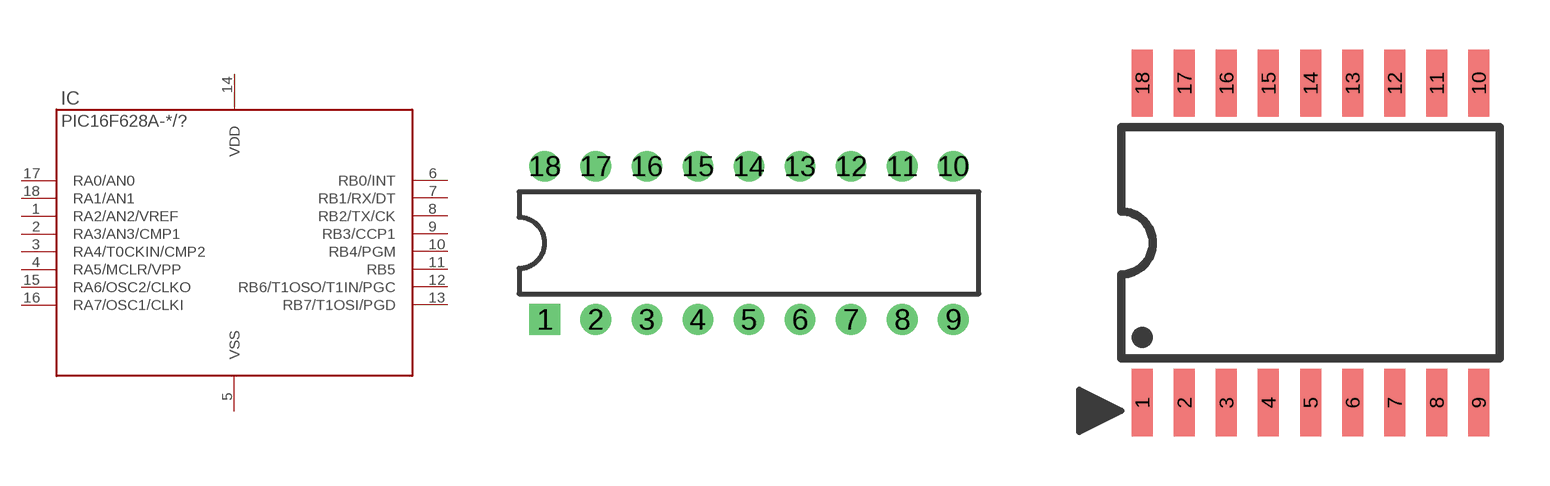
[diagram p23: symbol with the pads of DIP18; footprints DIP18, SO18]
Designator prefix IC

## PIC16F628A-E/P, PIC16F628A-I/P  [DIP18]
1  RA2/AN2/VREF
2  RA3/AN3/CMP1
3  RA4/T0CKIN/CMP2  in
4  RA5/MCLR/VPP
5  VSS  pwr
6  RB0/INT
7  RB1/RX/DT
8  RB2/TX/CK
9  RB3/CCP1
10  RB4/PGM
11  RB5
12  RB6/T1OSO/T1IN/PGC
13  RB7/T1OSI/PGD
14  VDD  pwr
15  RA6/OSC2/CLKO
16  RA7/OSC1/CLKI
17  RA0/AN0
18  RA1/AN1

## PIC16F628A-E/SO, PIC16F628A-I/SO  [SO18]
Pads as for DIP18

## Footprint DIP18 (pad centres in mm)
18 pin DIP package, P suffix
drill 0.737 pad 1.524 square: 1 -10.16,-3.81
drill 0.737 pad 1.524 round: 2 -7.62,-3.81; 3 -5.08,-3.81; 4 -2.54,-3.81; 5 0,-3.81; 6 2.54,-3.81; 7 5.08,-3.81; 8 7.62,-3.81; 9 10.16,-3.81; 10 10.16,3.81; 11 7.62,3.81; 12 5.08,3.81; 13 2.54,3.81; 14 0,3.81; 15 -2.54,3.81; 16 -5.08,3.81; 17 -7.62,3.81; 18 -10.16,3.81

## Footprint SO18 (pad centres in mm)
18 pin SOIC (SO suffix)
smd 0.635 x 2.032: 1 -5.08,-4.826; 2 -3.81,-4.826; 3 -2.54,-4.826; 4 -1.27,-4.826; 5 0,-4.826; 6 1.27,-4.826; 7 2.54,-4.826; 8 3.81,-4.826; 9 5.08,-4.826; 10 5.08,4.826; 11 3.81,4.826; 12 2.54,4.826; 13 1.27,4.826; 14 0,4.826; 15 -1.27,4.826; 16 -2.54,4.826; 17 -3.81,4.826; 18 -5.08,4.826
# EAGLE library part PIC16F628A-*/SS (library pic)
20 pins, 2K prog, 224 RAM, 128 EEPROM, UART, 2 comp, 1CCP

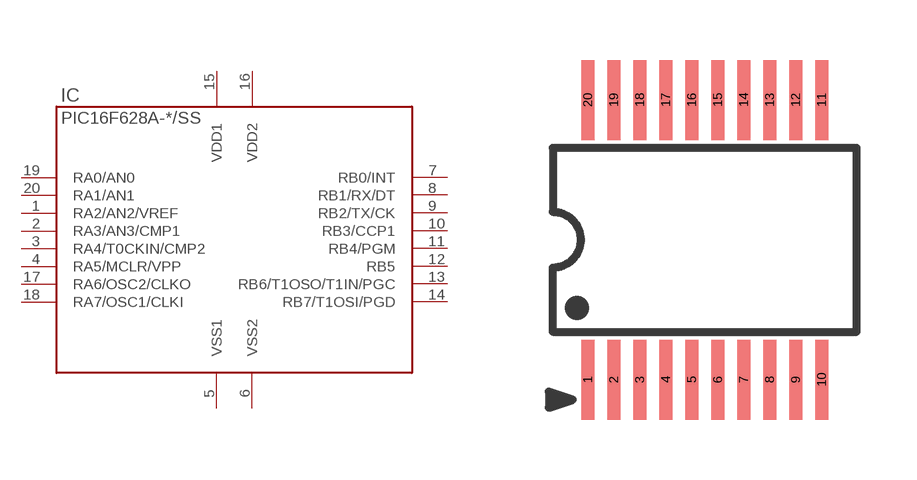
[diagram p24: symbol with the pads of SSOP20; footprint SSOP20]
Designator prefix IC

## PIC16F628A-E/SS, PIC16F628A-I/SS  [SSOP20]
1  RA2/AN2/VREF
2  RA3/AN3/CMP1
3  RA4/T0CKIN/CMP2  in
4  RA5/MCLR/VPP
5  VSS1  pwr
6  VSS2  pwr
7  RB0/INT
8  RB1/RX/DT
9  RB2/TX/CK
10  RB3/CCP1
11  RB4/PGM
12  RB5
13  RB6/T1OSO/T1IN/PGC
14  RB7/T1OSI/PGD
15  VDD1  pwr
16  VDD2  pwr
17  RA6/OSC2/CLKO
18  RA7/OSC1/CLKI
19  RA0/AN0
20  RA1/AN1

## Footprint SSOP20 (pad centres in mm)
20 pin SSOP (SS suffix)
smd 0.325 x 2: 1 -2.925,-3.5; 2 -2.275,-3.5; 3 -1.625,-3.5; 4 -0.975,-3.5; 5 -0.325,-3.5; 6 0.325,-3.5; 7 0.975,-3.5; 8 1.625,-3.5; 9 2.275,-3.5; 10 2.925,-3.5; 11 2.925,3.5; 12 2.275,3.5; 13 1.625,3.5; 14 0.975,3.5; 15 0.325,3.5; 16 -0.325,3.5; 17 -0.975,3.5; 18 -1.625,3.5; 19 -2.275,3.5; 20 -2.925,3.5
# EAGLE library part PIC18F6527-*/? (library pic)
64 pins, 24Kw prog, 3963 data, 1K EE, 12 A/D, 2 comp, 5 CCP, 2 UART, 2 MSSP

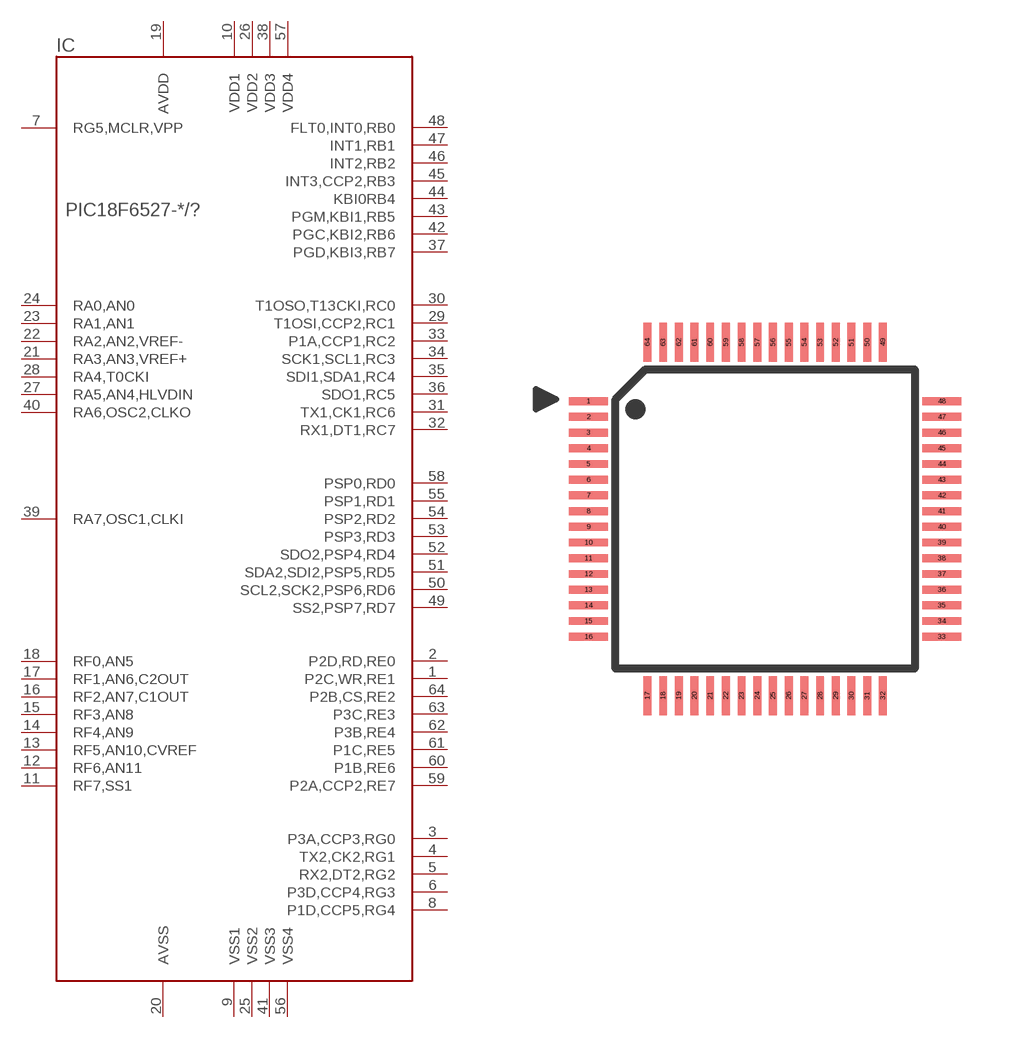
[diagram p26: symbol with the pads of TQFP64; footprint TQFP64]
Designator prefix IC

## PIC18F6527-E/PT, PIC18F6527-I/PT  [TQFP64]
1  P2C,WR,RE1
2  P2D,RD,RE0
3  P3A,CCP3,RG0
4  TX2,CK2,RG1
5  RX2,DT2,RG2
6  P3D,CCP4,RG3
7  RG5,MCLR,VPP  in
8  P1D,CCP5,RG4
9  VSS1  pwr
10  VDD1  pwr
11  RF7,SS1
12  RF6,AN11
13  RF5,AN10,CVREF
14  RF4,AN9
15  RF3,AN8
16  RF2,AN7,C1OUT
17  RF1,AN6,C2OUT
18  RF0,AN5
19  AVDD  pwr
20  AVSS  pwr
21  RA3,AN3,VREF+
22  RA2,AN2,VREF-
23  RA1,AN1
24  RA0,AN0
25  VSS2  pwr
26  VDD2  pwr
27  RA5,AN4,HLVDIN
28  RA4,T0CKI
29  T1OSI,CCP2,RC1
30  T1OSO,T13CKI,RC0
31  TX1,CK1,RC6
32  RX1,DT1,RC7
33  P1A,CCP1,RC2
34  SCK1,SCL1,RC3
35  SDI1,SDA1,RC4
36  SDO1,RC5
37  PGD,KBI3,RB7
38  VDD3  pwr
39  RA7,OSC1,CLKI  in
40  RA6,OSC2,CLKO
41  VSS3  pwr
42  PGC,KBI2,RB6
43  PGM,KBI1,RB5
44  KBI0RB4
45  INT3,CCP2,RB3
46  INT2,RB2
47  INT1,RB1
48  FLT0,INT0,RB0
49  SS2,PSP7,RD7
50  SCL2,SCK2,PSP6,RD6
51  SDA2,SDI2,PSP5,RD5
52  SDO2,PSP4,RD4
53  PSP3,RD3
54  PSP2,RD2
55  PSP1,RD1
56  VSS4  pwr
57  VDD4  pwr
58  PSP0,RD0
59  P2A,CCP2,RE7
60  P1B,RE6
61  P1C,RE5
62  P3B,RE4
63  P3C,RE3
64  P2B,CS,RE2

## Footprint TQFP64 (pad centres in mm)
64 pin TQFP (PT suffix)
smd 1.25 x 0.25: 1 -5.625,3.75; 2 -5.625,3.25; 3 -5.625,2.75; 4 -5.625,2.25; 5 -5.625,1.75; 6 -5.625,1.25; 7 -5.625,0.75; 8 -5.625,0.25; 9 -5.625,-0.25; 10 -5.625,-0.75; 11 -5.625,-1.25; 12 -5.625,-1.75; 13 -5.625,-2.25; 14 -5.625,-2.75; 15 -5.625,-3.25; 16 -5.625,-3.75; 33 5.625,-3.75; 34 5.625,-3.25; 35 5.625,-2.75; 36 5.625,-2.25; 37 5.625,-1.75; 38 5.625,-1.25; 39 5.625,-0.75; 40 5.625,-0.25; 41 5.625,0.25; 42 5.625,0.75; 43 5.625,1.25; 44 5.625,1.75; 45 5.625,2.25; 46 5.625,2.75; 47 5.625,3.25; 48 5.625,3.75
smd 0.25 x 1.25: 17 -3.75,-5.625; 18 -3.25,-5.625; 19 -2.75,-5.625; 20 -2.25,-5.625; 21 -1.75,-5.625; 22 -1.25,-5.625; 23 -0.75,-5.625; 24 -0.25,-5.625; 25 0.25,-5.625; 26 0.75,-5.625; 27 1.25,-5.625; 28 1.75,-5.625; 29 2.25,-5.625; 30 2.75,-5.625; 31 3.25,-5.625; 32 3.75,-5.625; 49 3.75,5.625; 50 3.25,5.625; 51 2.75,5.625; 52 2.25,5.625; 53 1.75,5.625; 54 1.25,5.625; 55 0.75,5.625; 56 0.25,5.625; 57 -0.25,5.625; 58 -0.75,5.625; 59 -1.25,5.625; 60 -1.75,5.625; 61 -2.25,5.625; 62 -2.75,5.625; 63 -3.25,5.625; 64 -3.75,5.625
